VERSION 5.7 ;
  NAMESCASESENSITIVE ON ;
  NOWIREEXTENSIONATPIN ON ;
  DIVIDERCHAR "/" ;
  BUSBITCHARS "[]" ;
UNITS
  DATABASE MICRONS 200 ;
END UNITS

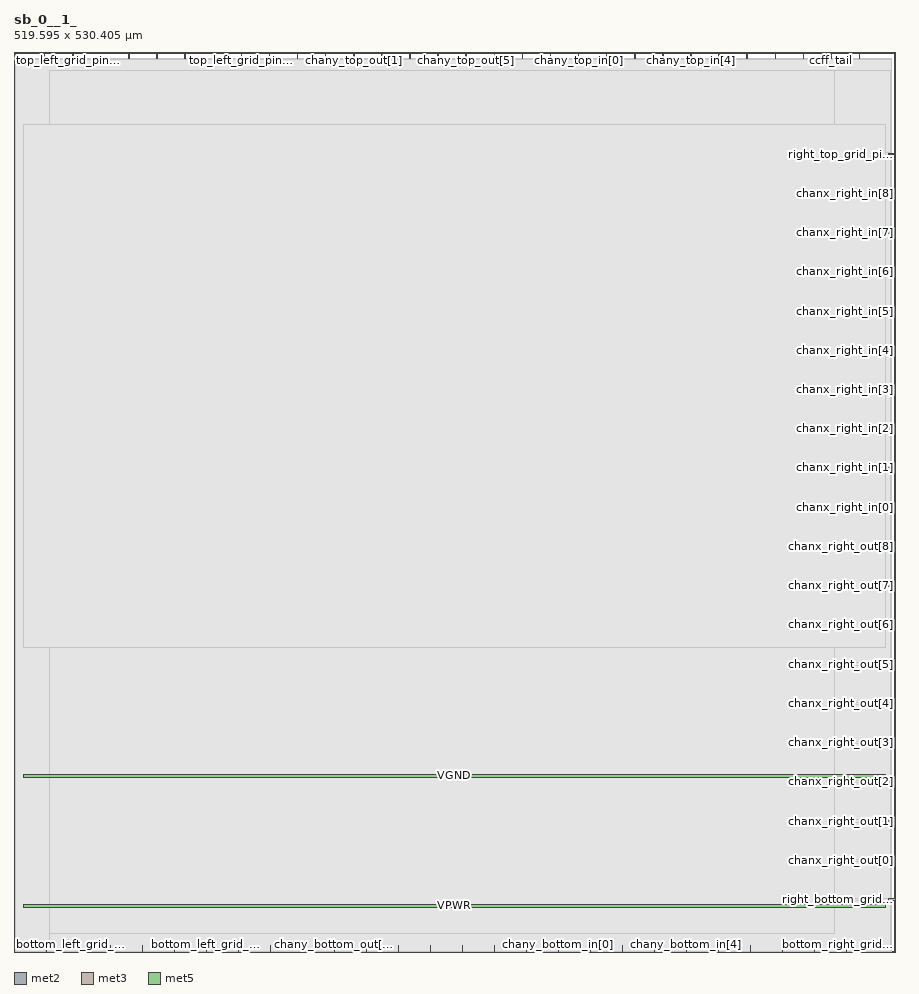
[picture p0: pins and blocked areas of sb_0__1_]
MACRO sb_0__1_
  CLASS BLOCK ;
  FOREIGN sb_0__1_ ;
  ORIGIN 0.000 0.000 ;
  SIZE 519.595 BY 530.405 ;
  PIN ccff_head
    DIRECTION INPUT ;
    PORT
      LAYER met2 ;
        RECT 1.380 526.405 1.660 530.405 ;
    END
  END ccff_head
  PIN top_left_grid_pin_1_
    DIRECTION INPUT ;
    PORT
      LAYER met2 ;
        RECT 17.940 526.405 18.220 530.405 ;
    END
  END top_left_grid_pin_1_
  PIN top_left_grid_pin_3_
    DIRECTION INPUT ;
    PORT
      LAYER met2 ;
        RECT 34.500 526.405 34.780 530.405 ;
    END
  END top_left_grid_pin_3_
  PIN top_left_grid_pin_5_
    DIRECTION INPUT ;
    PORT
      LAYER met2 ;
        RECT 51.060 526.405 51.340 530.405 ;
    END
  END top_left_grid_pin_5_
  PIN top_left_grid_pin_7_
    DIRECTION INPUT ;
    PORT
      LAYER met2 ;
        RECT 67.620 526.405 67.900 530.405 ;
    END
  END top_left_grid_pin_7_
  PIN top_left_grid_pin_9_
    DIRECTION INPUT ;
    PORT
      LAYER met2 ;
        RECT 84.180 526.405 84.460 530.405 ;
    END
  END top_left_grid_pin_9_
  PIN top_left_grid_pin_11_
    DIRECTION INPUT ;
    PORT
      LAYER met2 ;
        RECT 100.740 526.405 101.020 530.405 ;
    END
  END top_left_grid_pin_11_
  PIN top_left_grid_pin_13_
    DIRECTION INPUT ;
    PORT
      LAYER met2 ;
        RECT 117.300 526.405 117.580 530.405 ;
    END
  END top_left_grid_pin_13_
  PIN top_left_grid_pin_15_
    DIRECTION OUTPUT TRISTATE ;
    PORT
      LAYER met2 ;
        RECT 133.860 526.405 134.140 530.405 ;
    END
  END top_left_grid_pin_15_
  PIN pReset
    DIRECTION INPUT ;
    PORT
      LAYER met2 ;
        RECT 150.420 526.405 150.700 530.405 ;
    END
  END pReset
  PIN prog_clk
    DIRECTION INPUT ;
    PORT
      LAYER met2 ;
        RECT 166.980 526.405 167.260 530.405 ;
    END
  END prog_clk
  PIN chany_top_out[0]
    DIRECTION OUTPUT TRISTATE ;
    PORT
      LAYER met2 ;
        RECT 183.540 526.405 183.820 530.405 ;
    END
  END chany_top_out[0]
  PIN chany_top_out[1]
    DIRECTION OUTPUT TRISTATE ;
    PORT
      LAYER met2 ;
        RECT 200.100 526.405 200.380 530.405 ;
    END
  END chany_top_out[1]
  PIN chany_top_out[2]
    DIRECTION OUTPUT TRISTATE ;
    PORT
      LAYER met2 ;
        RECT 216.660 526.405 216.940 530.405 ;
    END
  END chany_top_out[2]
  PIN chany_top_out[3]
    DIRECTION OUTPUT TRISTATE ;
    PORT
      LAYER met2 ;
        RECT 233.220 526.405 233.500 530.405 ;
    END
  END chany_top_out[3]
  PIN chany_top_out[4]
    DIRECTION OUTPUT TRISTATE ;
    PORT
      LAYER met2 ;
        RECT 249.780 526.405 250.060 530.405 ;
    END
  END chany_top_out[4]
  PIN chany_top_out[5]
    DIRECTION OUTPUT TRISTATE ;
    PORT
      LAYER met2 ;
        RECT 266.340 526.405 266.620 530.405 ;
    END
  END chany_top_out[5]
  PIN chany_top_out[6]
    DIRECTION OUTPUT TRISTATE ;
    PORT
      LAYER met2 ;
        RECT 282.900 526.405 283.180 530.405 ;
    END
  END chany_top_out[6]
  PIN chany_top_out[7]
    DIRECTION OUTPUT TRISTATE ;
    PORT
      LAYER met2 ;
        RECT 299.460 526.405 299.740 530.405 ;
    END
  END chany_top_out[7]
  PIN chany_top_out[8]
    DIRECTION OUTPUT TRISTATE ;
    PORT
      LAYER met2 ;
        RECT 316.020 526.405 316.300 530.405 ;
    END
  END chany_top_out[8]
  PIN chany_top_in[0]
    DIRECTION INPUT ;
    PORT
      LAYER met2 ;
        RECT 332.580 526.405 332.860 530.405 ;
    END
  END chany_top_in[0]
  PIN chany_top_in[1]
    DIRECTION INPUT ;
    PORT
      LAYER met2 ;
        RECT 349.140 526.405 349.420 530.405 ;
    END
  END chany_top_in[1]
  PIN chany_top_in[2]
    DIRECTION INPUT ;
    PORT
      LAYER met2 ;
        RECT 365.700 526.405 365.980 530.405 ;
    END
  END chany_top_in[2]
  PIN chany_top_in[3]
    DIRECTION INPUT ;
    PORT
      LAYER met2 ;
        RECT 382.260 526.405 382.540 530.405 ;
    END
  END chany_top_in[3]
  PIN chany_top_in[4]
    DIRECTION INPUT ;
    PORT
      LAYER met2 ;
        RECT 398.820 526.405 399.100 530.405 ;
    END
  END chany_top_in[4]
  PIN chany_top_in[5]
    DIRECTION INPUT ;
    PORT
      LAYER met2 ;
        RECT 415.380 526.405 415.660 530.405 ;
    END
  END chany_top_in[5]
  PIN chany_top_in[6]
    DIRECTION INPUT ;
    PORT
      LAYER met2 ;
        RECT 431.940 526.405 432.220 530.405 ;
    END
  END chany_top_in[6]
  PIN chany_top_in[7]
    DIRECTION INPUT ;
    PORT
      LAYER met2 ;
        RECT 448.500 526.405 448.780 530.405 ;
    END
  END chany_top_in[7]
  PIN chany_top_in[8]
    DIRECTION INPUT ;
    PORT
      LAYER met2 ;
        RECT 465.060 526.405 465.340 530.405 ;
    END
  END chany_top_in[8]
  PIN ccff_tail
    DIRECTION OUTPUT TRISTATE ;
    PORT
      LAYER met2 ;
        RECT 481.620 526.405 481.900 530.405 ;
    END
  END ccff_tail
  PIN top_right_grid_pin_11_
    DIRECTION INPUT ;
    PORT
      LAYER met2 ;
        RECT 498.180 526.405 498.460 530.405 ;
    END
  END top_right_grid_pin_11_
  PIN right_bottom_grid_pin_12_
    DIRECTION INPUT ;
    PORT
      LAYER met3 ;
        RECT 515.595 30.640 519.595 31.240 ;
    END
  END right_bottom_grid_pin_12_
  PIN chanx_right_out[0]
    DIRECTION OUTPUT TRISTATE ;
    PORT
      LAYER met3 ;
        RECT 515.595 53.760 519.595 54.360 ;
    END
  END chanx_right_out[0]
  PIN chanx_right_out[1]
    DIRECTION OUTPUT TRISTATE ;
    PORT
      LAYER met3 ;
        RECT 515.595 76.880 519.595 77.480 ;
    END
  END chanx_right_out[1]
  PIN chanx_right_out[2]
    DIRECTION OUTPUT TRISTATE ;
    PORT
      LAYER met3 ;
        RECT 515.595 100.000 519.595 100.600 ;
    END
  END chanx_right_out[2]
  PIN chanx_right_out[3]
    DIRECTION OUTPUT TRISTATE ;
    PORT
      LAYER met3 ;
        RECT 515.595 123.120 519.595 123.720 ;
    END
  END chanx_right_out[3]
  PIN chanx_right_out[4]
    DIRECTION OUTPUT TRISTATE ;
    PORT
      LAYER met3 ;
        RECT 515.595 146.240 519.595 146.840 ;
    END
  END chanx_right_out[4]
  PIN chanx_right_out[5]
    DIRECTION OUTPUT TRISTATE ;
    PORT
      LAYER met3 ;
        RECT 515.595 169.360 519.595 169.960 ;
    END
  END chanx_right_out[5]
  PIN chanx_right_out[6]
    DIRECTION OUTPUT TRISTATE ;
    PORT
      LAYER met3 ;
        RECT 515.595 192.480 519.595 193.080 ;
    END
  END chanx_right_out[6]
  PIN chanx_right_out[7]
    DIRECTION OUTPUT TRISTATE ;
    PORT
      LAYER met3 ;
        RECT 515.595 215.600 519.595 216.200 ;
    END
  END chanx_right_out[7]
  PIN chanx_right_out[8]
    DIRECTION OUTPUT TRISTATE ;
    PORT
      LAYER met3 ;
        RECT 515.595 238.720 519.595 239.320 ;
    END
  END chanx_right_out[8]
  PIN chanx_right_in[0]
    DIRECTION INPUT ;
    PORT
      LAYER met3 ;
        RECT 515.595 261.840 519.595 262.440 ;
    END
  END chanx_right_in[0]
  PIN chanx_right_in[1]
    DIRECTION INPUT ;
    PORT
      LAYER met3 ;
        RECT 515.595 284.960 519.595 285.560 ;
    END
  END chanx_right_in[1]
  PIN chanx_right_in[2]
    DIRECTION INPUT ;
    PORT
      LAYER met3 ;
        RECT 515.595 308.080 519.595 308.680 ;
    END
  END chanx_right_in[2]
  PIN chanx_right_in[3]
    DIRECTION INPUT ;
    PORT
      LAYER met3 ;
        RECT 515.595 331.200 519.595 331.800 ;
    END
  END chanx_right_in[3]
  PIN chanx_right_in[4]
    DIRECTION INPUT ;
    PORT
      LAYER met3 ;
        RECT 515.595 354.320 519.595 354.920 ;
    END
  END chanx_right_in[4]
  PIN chanx_right_in[5]
    DIRECTION INPUT ;
    PORT
      LAYER met3 ;
        RECT 515.595 377.440 519.595 378.040 ;
    END
  END chanx_right_in[5]
  PIN chanx_right_in[6]
    DIRECTION INPUT ;
    PORT
      LAYER met3 ;
        RECT 515.595 400.560 519.595 401.160 ;
    END
  END chanx_right_in[6]
  PIN chanx_right_in[7]
    DIRECTION INPUT ;
    PORT
      LAYER met3 ;
        RECT 515.595 423.680 519.595 424.280 ;
    END
  END chanx_right_in[7]
  PIN chanx_right_in[8]
    DIRECTION INPUT ;
    PORT
      LAYER met3 ;
        RECT 515.595 446.800 519.595 447.400 ;
    END
  END chanx_right_in[8]
  PIN right_top_grid_pin_10_
    DIRECTION INPUT ;
    PORT
      LAYER met3 ;
        RECT 515.595 469.920 519.595 470.520 ;
    END
  END right_top_grid_pin_10_
  PIN bottom_left_grid_pin_1_
    DIRECTION INPUT ;
    PORT
      LAYER met2 ;
        RECT 0.000 0.000 0.280 4.000 ;
    END
  END bottom_left_grid_pin_1_
  PIN bottom_left_grid_pin_3_
    DIRECTION INPUT ;
    PORT
      LAYER met2 ;
        RECT 18.860 0.000 19.140 4.000 ;
    END
  END bottom_left_grid_pin_3_
  PIN bottom_left_grid_pin_5_
    DIRECTION INPUT ;
    PORT
      LAYER met2 ;
        RECT 37.720 0.000 38.000 4.000 ;
    END
  END bottom_left_grid_pin_5_
  PIN bottom_left_grid_pin_7_
    DIRECTION INPUT ;
    PORT
      LAYER met2 ;
        RECT 56.580 0.000 56.860 4.000 ;
    END
  END bottom_left_grid_pin_7_
  PIN bottom_left_grid_pin_9_
    DIRECTION INPUT ;
    PORT
      LAYER met2 ;
        RECT 75.440 0.000 75.720 4.000 ;
    END
  END bottom_left_grid_pin_9_
  PIN bottom_left_grid_pin_11_
    DIRECTION INPUT ;
    PORT
      LAYER met2 ;
        RECT 94.300 0.000 94.580 4.000 ;
    END
  END bottom_left_grid_pin_11_
  PIN bottom_left_grid_pin_13_
    DIRECTION INPUT ;
    PORT
      LAYER met2 ;
        RECT 113.160 0.000 113.440 4.000 ;
    END
  END bottom_left_grid_pin_13_
  PIN bottom_left_grid_pin_15_
    DIRECTION INPUT ;
    PORT
      LAYER met2 ;
        RECT 132.020 0.000 132.300 4.000 ;
    END
  END bottom_left_grid_pin_15_
  PIN chany_bottom_out[0]
    DIRECTION OUTPUT TRISTATE ;
    PORT
      LAYER met2 ;
        RECT 150.880 0.000 151.160 4.000 ;
    END
  END chany_bottom_out[0]
  PIN chany_bottom_out[1]
    DIRECTION OUTPUT TRISTATE ;
    PORT
      LAYER met2 ;
        RECT 169.740 0.000 170.020 4.000 ;
    END
  END chany_bottom_out[1]
  PIN chany_bottom_out[2]
    DIRECTION OUTPUT TRISTATE ;
    PORT
      LAYER met2 ;
        RECT 188.600 0.000 188.880 4.000 ;
    END
  END chany_bottom_out[2]
  PIN chany_bottom_out[3]
    DIRECTION OUTPUT TRISTATE ;
    PORT
      LAYER met2 ;
        RECT 207.460 0.000 207.740 4.000 ;
    END
  END chany_bottom_out[3]
  PIN chany_bottom_out[4]
    DIRECTION OUTPUT TRISTATE ;
    PORT
      LAYER met2 ;
        RECT 226.320 0.000 226.600 4.000 ;
    END
  END chany_bottom_out[4]
  PIN chany_bottom_out[5]
    DIRECTION OUTPUT TRISTATE ;
    PORT
      LAYER met2 ;
        RECT 245.180 0.000 245.460 4.000 ;
    END
  END chany_bottom_out[5]
  PIN chany_bottom_out[6]
    DIRECTION OUTPUT TRISTATE ;
    PORT
      LAYER met2 ;
        RECT 264.040 0.000 264.320 4.000 ;
    END
  END chany_bottom_out[6]
  PIN chany_bottom_out[7]
    DIRECTION OUTPUT TRISTATE ;
    PORT
      LAYER met2 ;
        RECT 282.900 0.000 283.180 4.000 ;
    END
  END chany_bottom_out[7]
  PIN chany_bottom_out[8]
    DIRECTION OUTPUT TRISTATE ;
    PORT
      LAYER met2 ;
        RECT 301.760 0.000 302.040 4.000 ;
    END
  END chany_bottom_out[8]
  PIN chany_bottom_in[0]
    DIRECTION INPUT ;
    PORT
      LAYER met2 ;
        RECT 320.620 0.000 320.900 4.000 ;
    END
  END chany_bottom_in[0]
  PIN chany_bottom_in[1]
    DIRECTION INPUT ;
    PORT
      LAYER met2 ;
        RECT 339.480 0.000 339.760 4.000 ;
    END
  END chany_bottom_in[1]
  PIN chany_bottom_in[2]
    DIRECTION INPUT ;
    PORT
      LAYER met2 ;
        RECT 358.340 0.000 358.620 4.000 ;
    END
  END chany_bottom_in[2]
  PIN chany_bottom_in[3]
    DIRECTION INPUT ;
    PORT
      LAYER met2 ;
        RECT 377.200 0.000 377.480 4.000 ;
    END
  END chany_bottom_in[3]
  PIN chany_bottom_in[4]
    DIRECTION INPUT ;
    PORT
      LAYER met2 ;
        RECT 396.060 0.000 396.340 4.000 ;
    END
  END chany_bottom_in[4]
  PIN chany_bottom_in[5]
    DIRECTION INPUT ;
    PORT
      LAYER met2 ;
        RECT 414.920 0.000 415.200 4.000 ;
    END
  END chany_bottom_in[5]
  PIN chany_bottom_in[6]
    DIRECTION INPUT ;
    PORT
      LAYER met2 ;
        RECT 433.780 0.000 434.060 4.000 ;
    END
  END chany_bottom_in[6]
  PIN chany_bottom_in[7]
    DIRECTION INPUT ;
    PORT
      LAYER met2 ;
        RECT 452.640 0.000 452.920 4.000 ;
    END
  END chany_bottom_in[7]
  PIN chany_bottom_in[8]
    DIRECTION INPUT ;
    PORT
      LAYER met2 ;
        RECT 471.500 0.000 471.780 4.000 ;
    END
  END chany_bottom_in[8]
  PIN bottom_right_grid_pin_11_
    DIRECTION INPUT ;
    PORT
      LAYER met2 ;
        RECT 490.360 0.000 490.640 4.000 ;
    END
  END bottom_right_grid_pin_11_
  PIN VPWR
    DIRECTION INPUT ;
    USE POWER ;
    PORT
      LAYER met5 ;
        RECT 5.430 26.490 513.730 28.090 ;
    END
  END VPWR
  PIN VGND
    DIRECTION INPUT ;
    USE GROUND ;
    PORT
      LAYER met5 ;
        RECT 5.430 103.080 513.730 104.680 ;
    END
  END VGND
  OBS
      LAYER li1 ;
        RECT 5.430 0.085 513.730 519.605 ;
      LAYER met1 ;
        RECT 0.900 0.040 516.420 519.760 ;
      LAYER met2 ;
        RECT 0.930 526.125 1.100 526.730 ;
        RECT 1.940 526.125 17.660 526.730 ;
        RECT 18.500 526.125 34.220 526.730 ;
        RECT 35.060 526.125 50.780 526.730 ;
        RECT 51.620 526.125 67.340 526.730 ;
        RECT 68.180 526.125 83.900 526.730 ;
        RECT 84.740 526.125 100.460 526.730 ;
        RECT 101.300 526.125 117.020 526.730 ;
        RECT 117.860 526.125 133.580 526.730 ;
        RECT 134.420 526.125 150.140 526.730 ;
        RECT 150.980 526.125 166.700 526.730 ;
        RECT 167.540 526.125 183.260 526.730 ;
        RECT 184.100 526.125 199.820 526.730 ;
        RECT 200.660 526.125 216.380 526.730 ;
        RECT 217.220 526.125 232.940 526.730 ;
        RECT 233.780 526.125 249.500 526.730 ;
        RECT 250.340 526.125 266.060 526.730 ;
        RECT 266.900 526.125 282.620 526.730 ;
        RECT 283.460 526.125 299.180 526.730 ;
        RECT 300.020 526.125 315.740 526.730 ;
        RECT 316.580 526.125 332.300 526.730 ;
        RECT 333.140 526.125 348.860 526.730 ;
        RECT 349.700 526.125 365.420 526.730 ;
        RECT 366.260 526.125 381.980 526.730 ;
        RECT 382.820 526.125 398.540 526.730 ;
        RECT 399.380 526.125 415.100 526.730 ;
        RECT 415.940 526.125 431.660 526.730 ;
        RECT 432.500 526.125 448.220 526.730 ;
        RECT 449.060 526.125 464.780 526.730 ;
        RECT 465.620 526.125 481.340 526.730 ;
        RECT 482.180 526.125 497.900 526.730 ;
        RECT 498.740 526.125 516.860 526.730 ;
        RECT 0.930 4.280 516.860 526.125 ;
        RECT 0.930 0.010 18.580 4.280 ;
        RECT 19.420 0.010 37.440 4.280 ;
        RECT 38.280 0.010 56.300 4.280 ;
        RECT 57.140 0.010 75.160 4.280 ;
        RECT 76.000 0.010 94.020 4.280 ;
        RECT 94.860 0.010 112.880 4.280 ;
        RECT 113.720 0.010 131.740 4.280 ;
        RECT 132.580 0.010 150.600 4.280 ;
        RECT 151.440 0.010 169.460 4.280 ;
        RECT 170.300 0.010 188.320 4.280 ;
        RECT 189.160 0.010 207.180 4.280 ;
        RECT 208.020 0.010 226.040 4.280 ;
        RECT 226.880 0.010 244.900 4.280 ;
        RECT 245.740 0.010 263.760 4.280 ;
        RECT 264.600 0.010 282.620 4.280 ;
        RECT 283.460 0.010 301.480 4.280 ;
        RECT 302.320 0.010 320.340 4.280 ;
        RECT 321.180 0.010 339.200 4.280 ;
        RECT 340.040 0.010 358.060 4.280 ;
        RECT 358.900 0.010 376.920 4.280 ;
        RECT 377.760 0.010 395.780 4.280 ;
        RECT 396.620 0.010 414.640 4.280 ;
        RECT 415.480 0.010 433.500 4.280 ;
        RECT 434.340 0.010 452.360 4.280 ;
        RECT 453.200 0.010 471.220 4.280 ;
        RECT 472.060 0.010 490.080 4.280 ;
        RECT 490.920 0.010 516.860 4.280 ;
      LAYER met3 ;
        RECT 20.950 470.920 516.640 519.685 ;
        RECT 20.950 469.520 515.195 470.920 ;
        RECT 20.950 447.800 516.640 469.520 ;
        RECT 20.950 446.400 515.195 447.800 ;
        RECT 20.950 424.680 516.640 446.400 ;
        RECT 20.950 423.280 515.195 424.680 ;
        RECT 20.950 401.560 516.640 423.280 ;
        RECT 20.950 400.160 515.195 401.560 ;
        RECT 20.950 378.440 516.640 400.160 ;
        RECT 20.950 377.040 515.195 378.440 ;
        RECT 20.950 355.320 516.640 377.040 ;
        RECT 20.950 353.920 515.195 355.320 ;
        RECT 20.950 332.200 516.640 353.920 ;
        RECT 20.950 330.800 515.195 332.200 ;
        RECT 20.950 309.080 516.640 330.800 ;
        RECT 20.950 307.680 515.195 309.080 ;
        RECT 20.950 285.960 516.640 307.680 ;
        RECT 20.950 284.560 515.195 285.960 ;
        RECT 20.950 262.840 516.640 284.560 ;
        RECT 20.950 261.440 515.195 262.840 ;
        RECT 20.950 239.720 516.640 261.440 ;
        RECT 20.950 238.320 515.195 239.720 ;
        RECT 20.950 216.600 516.640 238.320 ;
        RECT 20.950 215.200 515.195 216.600 ;
        RECT 20.950 193.480 516.640 215.200 ;
        RECT 20.950 192.080 515.195 193.480 ;
        RECT 20.950 170.360 516.640 192.080 ;
        RECT 20.950 168.960 515.195 170.360 ;
        RECT 20.950 147.240 516.640 168.960 ;
        RECT 20.950 145.840 515.195 147.240 ;
        RECT 20.950 124.120 516.640 145.840 ;
        RECT 20.950 122.720 515.195 124.120 ;
        RECT 20.950 101.000 516.640 122.720 ;
        RECT 20.950 99.600 515.195 101.000 ;
        RECT 20.950 77.880 516.640 99.600 ;
        RECT 20.950 76.480 515.195 77.880 ;
        RECT 20.950 54.760 516.640 76.480 ;
        RECT 20.950 53.360 515.195 54.760 ;
        RECT 20.950 31.640 516.640 53.360 ;
        RECT 20.950 30.240 515.195 31.640 ;
        RECT 20.950 0.175 516.640 30.240 ;
      LAYER met4 ;
        RECT 20.950 10.640 483.350 519.760 ;
      LAYER met5 ;
        RECT 5.430 179.670 513.730 487.630 ;
  END
END sb_0__1_
END LIBRARY

